VERSION 5.7 ;
  NOWIREEXTENSIONATPIN ON ;
  DIVIDERCHAR "/" ;
  BUSBITCHARS "[]" ;
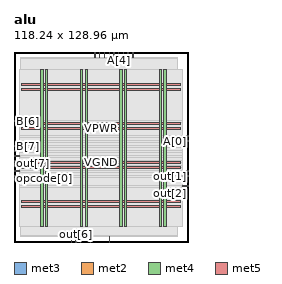
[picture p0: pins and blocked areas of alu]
MACRO alu
  CLASS BLOCK ;
  FOREIGN alu ;
  ORIGIN 0.000 0.000 ;
  SIZE 118.240 BY 128.960 ;
  PIN A[0]
    DIRECTION INPUT ;
    USE SIGNAL ;
    ANTENNAGATEAREA 0.159000 ;
    PORT
      LAYER met3 ;
        RECT 114.240 68.040 118.240 68.640 ;
    END
  END A[0]
  PIN A[1]
    DIRECTION INPUT ;
    USE SIGNAL ;
    ANTENNAGATEAREA 0.159000 ;
    PORT
      LAYER met3 ;
        RECT 114.240 71.440 118.240 72.040 ;
    END
  END A[1]
  PIN A[2]
    DIRECTION INPUT ;
    USE SIGNAL ;
    ANTENNAGATEAREA 0.213000 ;
    PORT
      LAYER met2 ;
        RECT 80.590 124.960 80.870 128.960 ;
    END
  END A[2]
  PIN A[3]
    DIRECTION INPUT ;
    USE SIGNAL ;
    ANTENNAGATEAREA 0.213000 ;
    PORT
      LAYER met2 ;
        RECT 77.370 124.960 77.650 128.960 ;
    END
  END A[3]
  PIN A[4]
    DIRECTION INPUT ;
    USE SIGNAL ;
    ANTENNAGATEAREA 0.495000 ;
    PORT
      LAYER met2 ;
        RECT 70.930 124.960 71.210 128.960 ;
    END
  END A[4]
  PIN A[5]
    DIRECTION INPUT ;
    USE SIGNAL ;
    ANTENNAGATEAREA 0.196500 ;
    PORT
      LAYER met2 ;
        RECT 64.490 124.960 64.770 128.960 ;
    END
  END A[5]
  PIN A[6]
    DIRECTION INPUT ;
    USE SIGNAL ;
    ANTENNAGATEAREA 0.213000 ;
    PORT
      LAYER met2 ;
        RECT 38.730 0.000 39.010 4.000 ;
    END
  END A[6]
  PIN A[7]
    DIRECTION INPUT ;
    USE SIGNAL ;
    ANTENNAGATEAREA 0.213000 ;
    PORT
      LAYER met3 ;
        RECT 0.000 61.240 4.000 61.840 ;
    END
  END A[7]
  PIN B[0]
    DIRECTION INPUT ;
    USE SIGNAL ;
    ANTENNAGATEAREA 0.495000 ;
    PORT
      LAYER met2 ;
        RECT 67.710 124.960 67.990 128.960 ;
    END
  END B[0]
  PIN B[1]
    DIRECTION INPUT ;
    USE SIGNAL ;
    ANTENNAGATEAREA 0.495000 ;
    PORT
      LAYER met2 ;
        RECT 74.150 124.960 74.430 128.960 ;
    END
  END B[1]
  PIN B[2]
    DIRECTION INPUT ;
    USE SIGNAL ;
    ANTENNAGATEAREA 0.213000 ;
    PORT
      LAYER met2 ;
        RECT 61.270 124.960 61.550 128.960 ;
    END
  END B[2]
  PIN B[3]
    DIRECTION INPUT ;
    USE SIGNAL ;
    ANTENNAGATEAREA 0.213000 ;
    PORT
      LAYER met2 ;
        RECT 58.050 124.960 58.330 128.960 ;
    END
  END B[3]
  PIN B[4]
    DIRECTION INPUT ;
    USE SIGNAL ;
    ANTENNAGATEAREA 0.196500 ;
    PORT
      LAYER met2 ;
        RECT 54.830 124.960 55.110 128.960 ;
    END
  END B[4]
  PIN B[5]
    DIRECTION INPUT ;
    USE SIGNAL ;
    ANTENNAGATEAREA 0.213000 ;
    PORT
      LAYER met2 ;
        RECT 45.170 0.000 45.450 4.000 ;
    END
  END B[5]
  PIN B[6]
    DIRECTION INPUT ;
    USE SIGNAL ;
    ANTENNAGATEAREA 0.159000 ;
    PORT
      LAYER met3 ;
        RECT 0.000 81.640 4.000 82.240 ;
    END
  END B[6]
  PIN B[7]
    DIRECTION INPUT ;
    USE SIGNAL ;
    ANTENNAGATEAREA 0.196500 ;
    PORT
      LAYER met3 ;
        RECT 0.000 64.640 4.000 65.240 ;
    END
  END B[7]
  PIN VGND
    DIRECTION INOUT ;
    USE GROUND ;
    PORT
      LAYER met4 ;
        RECT 21.415 10.640 23.015 117.200 ;
    END
    PORT
      LAYER met4 ;
        RECT 48.210 10.640 49.810 117.200 ;
    END
    PORT
      LAYER met4 ;
        RECT 75.005 10.640 76.605 117.200 ;
    END
    PORT
      LAYER met4 ;
        RECT 101.800 10.640 103.400 117.200 ;
    END
    PORT
      LAYER met5 ;
        RECT 5.280 26.640 112.940 28.240 ;
    END
    PORT
      LAYER met5 ;
        RECT 5.280 53.160 112.940 54.760 ;
    END
    PORT
      LAYER met5 ;
        RECT 5.280 79.680 112.940 81.280 ;
    END
    PORT
      LAYER met5 ;
        RECT 5.280 106.200 112.940 107.800 ;
    END
  END VGND
  PIN VPWR
    DIRECTION INOUT ;
    USE POWER ;
    PORT
      LAYER met4 ;
        RECT 18.115 10.640 19.715 117.200 ;
    END
    PORT
      LAYER met4 ;
        RECT 44.910 10.640 46.510 117.200 ;
    END
    PORT
      LAYER met4 ;
        RECT 71.705 10.640 73.305 117.200 ;
    END
    PORT
      LAYER met4 ;
        RECT 98.500 10.640 100.100 117.200 ;
    END
    PORT
      LAYER met5 ;
        RECT 5.280 23.340 112.940 24.940 ;
    END
    PORT
      LAYER met5 ;
        RECT 5.280 49.860 112.940 51.460 ;
    END
    PORT
      LAYER met5 ;
        RECT 5.280 76.380 112.940 77.980 ;
    END
    PORT
      LAYER met5 ;
        RECT 5.280 102.900 112.940 104.500 ;
    END
  END VPWR
  PIN opcode[0]
    DIRECTION INPUT ;
    USE SIGNAL ;
    ANTENNAGATEAREA 0.196500 ;
    PORT
      LAYER met3 ;
        RECT 0.000 47.640 4.000 48.240 ;
    END
  END opcode[0]
  PIN opcode[1]
    DIRECTION INPUT ;
    USE SIGNAL ;
    ANTENNAGATEAREA 0.213000 ;
    PORT
      LAYER met3 ;
        RECT 0.000 44.240 4.000 44.840 ;
    END
  END opcode[1]
  PIN opcode[2]
    DIRECTION INPUT ;
    USE SIGNAL ;
    ANTENNAGATEAREA 0.159000 ;
    PORT
      LAYER met3 ;
        RECT 0.000 51.040 4.000 51.640 ;
    END
  END opcode[2]
  PIN out[0]
    DIRECTION OUTPUT ;
    USE SIGNAL ;
    ANTENNADIFFAREA 0.445500 ;
    PORT
      LAYER met3 ;
        RECT 0.000 54.440 4.000 55.040 ;
    END
  END out[0]
  PIN out[1]
    DIRECTION OUTPUT ;
    USE SIGNAL ;
    ANTENNADIFFAREA 0.445500 ;
    PORT
      LAYER met3 ;
        RECT 114.240 44.240 118.240 44.840 ;
    END
  END out[1]
  PIN out[2]
    DIRECTION OUTPUT ;
    USE SIGNAL ;
    ANTENNADIFFAREA 0.445500 ;
    PORT
      LAYER met3 ;
        RECT 114.240 37.440 118.240 38.040 ;
    END
  END out[2]
  PIN out[3]
    DIRECTION OUTPUT ;
    USE SIGNAL ;
    ANTENNADIFFAREA 0.445500 ;
    PORT
      LAYER met3 ;
        RECT 114.240 47.640 118.240 48.240 ;
    END
  END out[3]
  PIN out[4]
    DIRECTION OUTPUT ;
    USE SIGNAL ;
    ANTENNADIFFAREA 0.445500 ;
    PORT
      LAYER met2 ;
        RECT 64.490 0.000 64.770 4.000 ;
    END
  END out[4]
  PIN out[5]
    DIRECTION OUTPUT ;
    USE SIGNAL ;
    ANTENNADIFFAREA 0.445500 ;
    PORT
      LAYER met2 ;
        RECT 51.610 0.000 51.890 4.000 ;
    END
  END out[5]
  PIN out[6]
    DIRECTION OUTPUT ;
    USE SIGNAL ;
    ANTENNADIFFAREA 0.445500 ;
    PORT
      LAYER met2 ;
        RECT 41.950 0.000 42.230 4.000 ;
    END
  END out[6]
  PIN out[7]
    DIRECTION OUTPUT ;
    USE SIGNAL ;
    ANTENNADIFFAREA 1.336500 ;
    PORT
      LAYER met3 ;
        RECT 0.000 57.840 4.000 58.440 ;
    END
  END out[7]
  OBS
      LAYER nwell ;
        RECT 5.330 10.795 112.890 117.150 ;
      LAYER li1 ;
        RECT 5.520 10.795 112.700 117.045 ;
      LAYER met1 ;
        RECT 4.210 10.640 112.700 117.200 ;
      LAYER met2 ;
        RECT 4.230 124.680 54.550 125.530 ;
        RECT 55.390 124.680 57.770 125.530 ;
        RECT 58.610 124.680 60.990 125.530 ;
        RECT 61.830 124.680 64.210 125.530 ;
        RECT 65.050 124.680 67.430 125.530 ;
        RECT 68.270 124.680 70.650 125.530 ;
        RECT 71.490 124.680 73.870 125.530 ;
        RECT 74.710 124.680 77.090 125.530 ;
        RECT 77.930 124.680 80.310 125.530 ;
        RECT 81.150 124.680 111.230 125.530 ;
        RECT 4.230 4.280 111.230 124.680 ;
        RECT 4.230 4.000 38.450 4.280 ;
        RECT 39.290 4.000 41.670 4.280 ;
        RECT 42.510 4.000 44.890 4.280 ;
        RECT 45.730 4.000 51.330 4.280 ;
        RECT 52.170 4.000 64.210 4.280 ;
        RECT 65.050 4.000 111.230 4.280 ;
      LAYER met3 ;
        RECT 3.990 82.640 114.240 117.125 ;
        RECT 4.400 81.240 114.240 82.640 ;
        RECT 3.990 72.440 114.240 81.240 ;
        RECT 3.990 71.040 113.840 72.440 ;
        RECT 3.990 69.040 114.240 71.040 ;
        RECT 3.990 67.640 113.840 69.040 ;
        RECT 3.990 65.640 114.240 67.640 ;
        RECT 4.400 64.240 114.240 65.640 ;
        RECT 3.990 62.240 114.240 64.240 ;
        RECT 4.400 60.840 114.240 62.240 ;
        RECT 3.990 58.840 114.240 60.840 ;
        RECT 4.400 57.440 114.240 58.840 ;
        RECT 3.990 55.440 114.240 57.440 ;
        RECT 4.400 54.040 114.240 55.440 ;
        RECT 3.990 52.040 114.240 54.040 ;
        RECT 4.400 50.640 114.240 52.040 ;
        RECT 3.990 48.640 114.240 50.640 ;
        RECT 4.400 47.240 113.840 48.640 ;
        RECT 3.990 45.240 114.240 47.240 ;
        RECT 4.400 43.840 113.840 45.240 ;
        RECT 3.990 38.440 114.240 43.840 ;
        RECT 3.990 37.040 113.840 38.440 ;
        RECT 3.990 10.715 114.240 37.040 ;
  END
END alu
END LIBRARY

